VERSION 5.7 ;
  NOWIREEXTENSIONATPIN ON ;
  DIVIDERCHAR "/" ;
  BUSBITCHARS "[]" ;
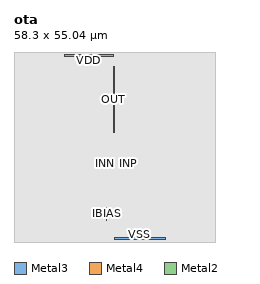
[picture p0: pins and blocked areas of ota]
MACRO ota
  CLASS BLOCK ;
  FOREIGN ota ;
  ORIGIN 29.260 3.940 ;
  SIZE 58.300 BY 55.040 ;
  PIN IBIAS
    ANTENNAGATEAREA 52.000000 ;
    ANTENNADIFFAREA 1.200000 ;
    PORT
      LAYER Metal3 ;
        RECT -2.600 2.300 -2.320 6.100 ;
    END
  END IBIAS
  PIN OUT
    ANTENNADIFFAREA 12.000000 ;
    PORT
      LAYER Metal4 ;
        RECT -0.560 27.800 -0.280 46.900 ;
    END
  END OUT
  PIN INN
    ANTENNAGATEAREA 12.000000 ;
    PORT
      LAYER Metal2 ;
        RECT -3.170 18.550 -2.890 18.830 ;
    END
  END INN
  PIN INP
    ANTENNAGATEAREA 12.000000 ;
    PORT
      LAYER Metal2 ;
        RECT 3.690 18.550 3.970 18.830 ;
    END
  END INP
  PIN VSS
    USE GROUND ;
    PORT
      LAYER Metal3 ;
        RECT -0.280 -3.220 14.740 -2.660 ;
    END
  END VSS
  PIN VDD
    USE POWER ;
    PORT
      LAYER Metal3 ;
        RECT -14.560 49.820 -0.560 50.380 ;
    END
  END VDD
  OBS
      LAYER Nwell ;
        RECT -26.040 0.000 26.040 46.770 ;
      LAYER Metal1 ;
        RECT -25.810 0.210 25.810 46.560 ;
      LAYER Metal2 ;
        RECT -26.170 19.130 26.350 48.310 ;
        RECT -26.170 18.250 -3.470 19.130 ;
        RECT -2.590 18.250 3.390 19.130 ;
        RECT 4.270 18.250 26.350 19.130 ;
        RECT -26.170 0.210 26.350 18.250 ;
      LAYER Metal3 ;
        RECT -29.260 49.520 -14.860 50.380 ;
        RECT -0.260 49.520 28.420 50.380 ;
        RECT -29.260 6.400 28.420 49.520 ;
        RECT -29.260 2.000 -2.900 6.400 ;
        RECT -2.020 2.000 28.420 6.400 ;
        RECT -29.260 -2.360 28.420 2.000 ;
        RECT -29.260 -2.660 -0.580 -2.360 ;
        RECT -29.260 -2.800 -0.280 -2.660 ;
        RECT -29.260 -3.080 -0.580 -2.800 ;
        RECT -29.260 -3.220 -0.280 -3.080 ;
        RECT 15.040 -3.220 28.420 -2.360 ;
      LAYER Metal4 ;
        RECT -29.230 47.200 28.390 50.350 ;
        RECT -29.230 27.500 -0.860 47.200 ;
        RECT 0.020 27.500 28.390 47.200 ;
        RECT -29.230 -3.190 28.390 27.500 ;
      LAYER Metal5 ;
        RECT -29.230 -3.940 29.040 51.100 ;
  END
END ota
END LIBRARY

